VERSION 5.7 ;
  NOWIREEXTENSIONATPIN ON ;
  DIVIDERCHAR "/" ;
  BUSBITCHARS "[]" ;
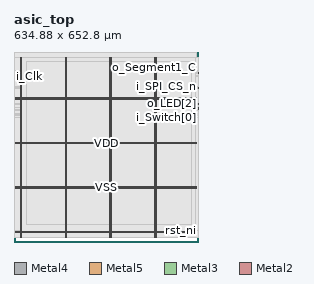
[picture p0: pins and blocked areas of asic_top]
MACRO asic_top
  CLASS BLOCK ;
  FOREIGN asic_top ;
  ORIGIN 0.000 0.000 ;
  SIZE 634.880 BY 652.800 ;
  PIN VDD
    DIRECTION INOUT ;
    USE POWER ;
    PORT
      LAYER Metal4 ;
        RECT 22.240 15.380 23.840 635.340 ;
    END
    PORT
      LAYER Metal4 ;
        RECT 175.840 15.380 177.440 635.340 ;
    END
    PORT
      LAYER Metal4 ;
        RECT 329.440 15.380 331.040 635.340 ;
    END
    PORT
      LAYER Metal4 ;
        RECT 483.040 15.380 484.640 635.340 ;
    END
    PORT
      LAYER Metal5 ;
        RECT 6.720 31.530 627.760 33.130 ;
    END
    PORT
      LAYER Metal5 ;
        RECT 6.720 184.710 627.760 186.310 ;
    END
    PORT
      LAYER Metal5 ;
        RECT 6.720 337.890 627.760 339.490 ;
    END
    PORT
      LAYER Metal5 ;
        RECT 6.720 491.070 627.760 492.670 ;
    END
  END VDD
  PIN VSS
    DIRECTION INOUT ;
    USE GROUND ;
    PORT
      LAYER Metal4 ;
        RECT 25.540 15.380 27.140 635.340 ;
    END
    PORT
      LAYER Metal4 ;
        RECT 179.140 15.380 180.740 635.340 ;
    END
    PORT
      LAYER Metal4 ;
        RECT 332.740 15.380 334.340 635.340 ;
    END
    PORT
      LAYER Metal4 ;
        RECT 486.340 15.380 487.940 635.340 ;
    END
    PORT
      LAYER Metal5 ;
        RECT 6.720 34.830 627.760 36.430 ;
    END
    PORT
      LAYER Metal5 ;
        RECT 6.720 188.010 627.760 189.610 ;
    END
    PORT
      LAYER Metal5 ;
        RECT 6.720 341.190 627.760 342.790 ;
    END
    PORT
      LAYER Metal5 ;
        RECT 6.720 494.370 627.760 495.970 ;
    END
  END VSS
  PIN i_Clk
    DIRECTION INPUT ;
    USE SIGNAL ;
    ANTENNAGATEAREA 4.738000 ;
    PORT
      LAYER Metal3 ;
        RECT 0.000 568.960 0.560 569.520 ;
    END
  END i_Clk
  PIN i_SPI_CS_n
    DIRECTION INPUT ;
    USE SIGNAL ;
    ANTENNAGATEAREA 0.396000 ;
    PORT
      LAYER Metal3 ;
        RECT 634.320 533.120 634.880 533.680 ;
    END
  END i_SPI_CS_n
  PIN i_SPI_MOSI
    DIRECTION INPUT ;
    USE SIGNAL ;
    ANTENNAGATEAREA 0.396000 ;
    PORT
      LAYER Metal2 ;
        RECT 479.360 652.240 479.920 652.800 ;
    END
  END i_SPI_MOSI
  PIN i_SPI_SCLK
    DIRECTION INPUT ;
    USE SIGNAL ;
    ANTENNAGATEAREA 0.396000 ;
    PORT
      LAYER Metal3 ;
        RECT 634.320 534.240 634.880 534.800 ;
    END
  END i_SPI_SCLK
  PIN i_Switch[0]
    DIRECTION INPUT ;
    USE SIGNAL ;
    ANTENNAGATEAREA 0.396000 ;
    PORT
      LAYER Metal3 ;
        RECT 634.320 426.720 634.880 427.280 ;
    END
  END i_Switch[0]
  PIN i_Switch[1]
    DIRECTION INPUT ;
    USE SIGNAL ;
    ANTENNAGATEAREA 0.396000 ;
    PORT
      LAYER Metal3 ;
        RECT 634.320 439.040 634.880 439.600 ;
    END
  END i_Switch[1]
  PIN i_Switch[2]
    DIRECTION INPUT ;
    USE SIGNAL ;
    ANTENNAGATEAREA 0.396000 ;
    PORT
      LAYER Metal3 ;
        RECT 634.320 435.680 634.880 436.240 ;
    END
  END i_Switch[2]
  PIN i_Switch[3]
    DIRECTION INPUT ;
    USE SIGNAL ;
    ANTENNAGATEAREA 0.396000 ;
    PORT
      LAYER Metal3 ;
        RECT 634.320 437.920 634.880 438.480 ;
    END
  END i_Switch[3]
  PIN o_LED[0]
    DIRECTION OUTPUT ;
    USE SIGNAL ;
    ANTENNADIFFAREA 0.897600 ;
    PORT
      LAYER Metal3 ;
        RECT 634.320 460.320 634.880 460.880 ;
    END
  END o_LED[0]
  PIN o_LED[1]
    DIRECTION OUTPUT ;
    USE SIGNAL ;
    ANTENNADIFFAREA 0.897600 ;
    PORT
      LAYER Metal3 ;
        RECT 634.320 459.200 634.880 459.760 ;
    END
  END o_LED[1]
  PIN o_LED[2]
    DIRECTION OUTPUT ;
    USE SIGNAL ;
    ANTENNADIFFAREA 0.897600 ;
    PORT
      LAYER Metal3 ;
        RECT 634.320 476.000 634.880 476.560 ;
    END
  END o_LED[2]
  PIN o_LED[3]
    DIRECTION OUTPUT ;
    USE SIGNAL ;
    ANTENNADIFFAREA 0.897600 ;
    PORT
      LAYER Metal3 ;
        RECT 634.320 472.640 634.880 473.200 ;
    END
  END o_LED[3]
  PIN o_SPI_MISO
    DIRECTION OUTPUT ;
    USE SIGNAL ;
    ANTENNADIFFAREA 0.897600 ;
    PORT
      LAYER Metal3 ;
        RECT 634.320 528.640 634.880 529.200 ;
    END
  END o_SPI_MISO
  PIN o_Segment1_A
    DIRECTION OUTPUT ;
    USE SIGNAL ;
    ANTENNADIFFAREA 0.897600 ;
    PORT
      LAYER Metal3 ;
        RECT 634.320 584.640 634.880 585.200 ;
    END
  END o_Segment1_A
  PIN o_Segment1_B
    DIRECTION OUTPUT ;
    USE SIGNAL ;
    ANTENNADIFFAREA 0.897600 ;
    PORT
      LAYER Metal3 ;
        RECT 634.320 585.760 634.880 586.320 ;
    END
  END o_Segment1_B
  PIN o_Segment1_C
    DIRECTION OUTPUT ;
    USE SIGNAL ;
    ANTENNADIFFAREA 0.897600 ;
    PORT
      LAYER Metal3 ;
        RECT 634.320 572.320 634.880 572.880 ;
    END
  END o_Segment1_C
  PIN o_Segment1_D
    DIRECTION OUTPUT ;
    USE SIGNAL ;
    ANTENNADIFFAREA 0.897600 ;
    PORT
      LAYER Metal3 ;
        RECT 634.320 588.000 634.880 588.560 ;
    END
  END o_Segment1_D
  PIN o_Segment1_E
    DIRECTION OUTPUT ;
    USE SIGNAL ;
    ANTENNADIFFAREA 0.897600 ;
    PORT
      LAYER Metal3 ;
        RECT 634.320 579.040 634.880 579.600 ;
    END
  END o_Segment1_E
  PIN o_Segment1_F
    DIRECTION OUTPUT ;
    USE SIGNAL ;
    ANTENNADIFFAREA 0.897600 ;
    PORT
      LAYER Metal3 ;
        RECT 634.320 583.520 634.880 584.080 ;
    END
  END o_Segment1_F
  PIN o_Segment1_G
    DIRECTION OUTPUT ;
    USE SIGNAL ;
    ANTENNADIFFAREA 0.897600 ;
    PORT
      LAYER Metal3 ;
        RECT 634.320 580.160 634.880 580.720 ;
    END
  END o_Segment1_G
  PIN o_Segment2_A
    DIRECTION OUTPUT ;
    USE SIGNAL ;
    ANTENNADIFFAREA 0.897600 ;
    PORT
      LAYER Metal3 ;
        RECT 634.320 458.080 634.880 458.640 ;
    END
  END o_Segment2_A
  PIN o_Segment2_B
    DIRECTION OUTPUT ;
    USE SIGNAL ;
    ANTENNADIFFAREA 0.897600 ;
    PORT
      LAYER Metal3 ;
        RECT 634.320 455.840 634.880 456.400 ;
    END
  END o_Segment2_B
  PIN o_Segment2_C
    DIRECTION OUTPUT ;
    USE SIGNAL ;
    ANTENNADIFFAREA 0.897600 ;
    PORT
      LAYER Metal3 ;
        RECT 634.320 473.760 634.880 474.320 ;
    END
  END o_Segment2_C
  PIN o_Segment2_D
    DIRECTION OUTPUT ;
    USE SIGNAL ;
    ANTENNADIFFAREA 0.897600 ;
    PORT
      LAYER Metal3 ;
        RECT 634.320 453.600 634.880 454.160 ;
    END
  END o_Segment2_D
  PIN o_Segment2_E
    DIRECTION OUTPUT ;
    USE SIGNAL ;
    ANTENNADIFFAREA 0.897600 ;
    PORT
      LAYER Metal3 ;
        RECT 634.320 456.960 634.880 457.520 ;
    END
  END o_Segment2_E
  PIN o_Segment2_F
    DIRECTION OUTPUT ;
    USE SIGNAL ;
    ANTENNADIFFAREA 0.897600 ;
    PORT
      LAYER Metal3 ;
        RECT 634.320 474.880 634.880 475.440 ;
    END
  END o_Segment2_F
  PIN o_Segment2_G
    DIRECTION OUTPUT ;
    USE SIGNAL ;
    ANTENNADIFFAREA 0.897600 ;
    PORT
      LAYER Metal3 ;
        RECT 634.320 471.520 634.880 472.080 ;
    END
  END o_Segment2_G
  PIN rst_ni
    DIRECTION INPUT ;
    USE SIGNAL ;
    ANTENNAGATEAREA 0.396000 ;
    PORT
      LAYER Metal3 ;
        RECT 634.320 40.320 634.880 40.880 ;
    END
  END rst_ni
  OBS
      LAYER Nwell ;
        RECT 6.290 15.250 628.190 635.470 ;
      LAYER Metal1 ;
        RECT 6.720 15.380 627.760 635.340 ;
      LAYER Metal2 ;
        RECT 0.140 651.940 479.060 652.240 ;
        RECT 480.220 651.940 626.500 652.240 ;
        RECT 0.140 15.490 626.500 651.940 ;
      LAYER Metal3 ;
        RECT 0.090 588.860 634.320 635.180 ;
        RECT 0.090 587.700 634.020 588.860 ;
        RECT 0.090 586.620 634.320 587.700 ;
        RECT 0.090 583.220 634.020 586.620 ;
        RECT 0.090 581.020 634.320 583.220 ;
        RECT 0.090 578.740 634.020 581.020 ;
        RECT 0.090 573.180 634.320 578.740 ;
        RECT 0.090 572.020 634.020 573.180 ;
        RECT 0.090 569.820 634.320 572.020 ;
        RECT 0.860 568.660 634.320 569.820 ;
        RECT 0.090 535.100 634.320 568.660 ;
        RECT 0.090 532.820 634.020 535.100 ;
        RECT 0.090 529.500 634.320 532.820 ;
        RECT 0.090 528.340 634.020 529.500 ;
        RECT 0.090 476.860 634.320 528.340 ;
        RECT 0.090 471.220 634.020 476.860 ;
        RECT 0.090 461.180 634.320 471.220 ;
        RECT 0.090 455.540 634.020 461.180 ;
        RECT 0.090 454.460 634.320 455.540 ;
        RECT 0.090 453.300 634.020 454.460 ;
        RECT 0.090 439.900 634.320 453.300 ;
        RECT 0.090 437.620 634.020 439.900 ;
        RECT 0.090 436.540 634.320 437.620 ;
        RECT 0.090 435.380 634.020 436.540 ;
        RECT 0.090 427.580 634.320 435.380 ;
        RECT 0.090 426.420 634.020 427.580 ;
        RECT 0.090 41.180 634.320 426.420 ;
        RECT 0.090 40.020 634.020 41.180 ;
        RECT 0.090 15.540 634.320 40.020 ;
      LAYER Metal4 ;
        RECT 24.220 37.610 25.240 632.710 ;
        RECT 27.440 37.610 175.540 632.710 ;
        RECT 177.740 37.610 178.840 632.710 ;
        RECT 181.040 37.610 329.140 632.710 ;
        RECT 331.340 37.610 332.440 632.710 ;
        RECT 334.640 37.610 482.740 632.710 ;
        RECT 484.940 37.610 486.040 632.710 ;
        RECT 488.240 37.610 622.020 632.710 ;
      LAYER Metal5 ;
        RECT 42.060 496.570 610.900 621.670 ;
        RECT 42.060 493.270 610.900 493.770 ;
        RECT 42.060 343.390 610.900 490.470 ;
        RECT 42.060 340.090 610.900 340.590 ;
        RECT 42.060 190.210 610.900 337.290 ;
        RECT 42.060 186.910 610.900 187.410 ;
        RECT 42.060 60.530 610.900 184.110 ;
  END
END asic_top
END LIBRARY

